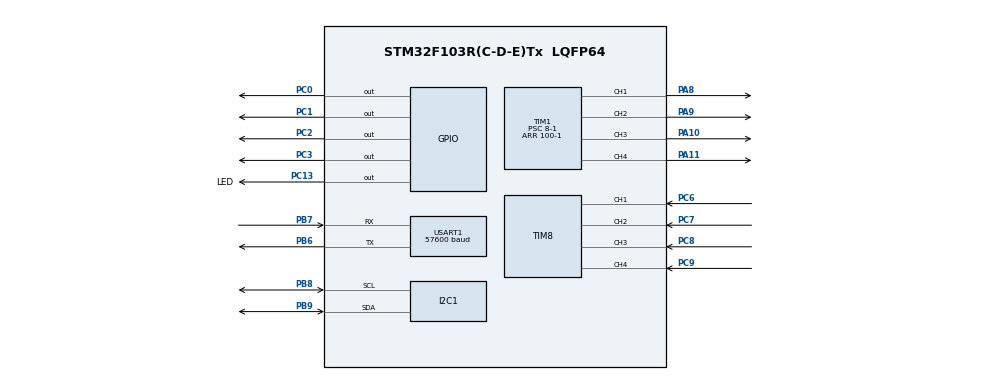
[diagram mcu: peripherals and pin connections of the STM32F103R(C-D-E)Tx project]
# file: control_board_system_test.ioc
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Dma.Request0=USART1_TX
Dma.Request1=USART1_RX
Dma.USART1_RX.1.Direction=DMA_PERIPH_TO_MEMORY
Dma.USART1_RX.1.Instance=DMA1_Channel5
Dma.USART1_RX.1.MemDataAlignment=DMA_MDATAALIGN_BYTE
Dma.USART1_RX.1.MemInc=DMA_MINC_ENABLE
Dma.USART1_RX.1.Mode=DMA_NORMAL
Dma.USART1_RX.1.PeriphDataAlignment=DMA_PDATAALIGN_BYTE
Dma.USART1_RX.1.PeriphInc=DMA_PINC_DISABLE
Dma.USART1_RX.1.Priority=DMA_PRIORITY_HIGH
Dma.USART1_TX.0.Direction=DMA_MEMORY_TO_PERIPH
Dma.USART1_TX.0.Instance=DMA1_Channel4
Dma.USART1_TX.0.MemDataAlignment=DMA_MDATAALIGN_BYTE
Dma.USART1_TX.0.MemInc=DMA_MINC_ENABLE
Dma.USART1_TX.0.Mode=DMA_NORMAL
Dma.USART1_TX.0.PeriphDataAlignment=DMA_PDATAALIGN_BYTE
Dma.USART1_TX.0.PeriphInc=DMA_PINC_DISABLE
Dma.USART1_TX.0.Priority=DMA_PRIORITY_HIGH
I2C1.I2C_Mode=I2C_Fast
Mcu.Family=STM32F1
Mcu.Name=STM32F103R(C-D-E)Tx
Mcu.Package=LQFP64
NVIC.DMA1_Channel4_IRQn=true\:0\:0\:false\:false\:true\:false\:true\:true
NVIC.DMA1_Channel5_IRQn=true\:0\:0\:false\:false\:true\:false\:true\:true
NVIC.PriorityGroup=NVIC_PRIORITYGROUP_4
NVIC.TIM8_CC_IRQn=true\:0\:0\:false\:false\:true\:true\:true\:true
NVIC.USART1_IRQn=true\:0\:0\:false\:false\:true\:true\:true\:true
PA10.Signal=S_TIM1_CH3
PA11.Signal=S_TIM1_CH4
PA13.Mode=Serial_Wire
PA13.Signal=SYS_JTMS-SWDIO
PA14.Mode=Serial_Wire
PA14.Signal=SYS_JTCK-SWCLK
PA8.Signal=S_TIM1_CH1
PA9.Signal=S_TIM1_CH2
PB6.Mode=Asynchronous
PB6.Signal=USART1_TX
PB7.Mode=Asynchronous
PB7.Signal=USART1_RX
PB8.Mode=I2C
PB8.Signal=I2C1_SCL
PB9.Mode=I2C
PB9.Signal=I2C1_SDA
PC0.Signal=GPIO_Output
PC1.Signal=GPIO_Output
PC13-TAMPER-RTC.GPIO_Label=LED
PC13-TAMPER-RTC.PinState=GPIO_PIN_SET
PC13-TAMPER-RTC.Signal=GPIO_Output
PC2.Signal=GPIO_Output
PC3.Signal=GPIO_Output
PC6.Signal=S_TIM8_CH1
PC7.Signal=S_TIM8_CH2
PC8.Signal=S_TIM8_CH3
PC9.Signal=S_TIM8_CH4
PD0-OSC_IN.Mode=HSE-External-Oscillator
PD0-OSC_IN.Signal=RCC_OSC_IN
PD1-OSC_OUT.Mode=HSE-External-Oscillator
PD1-OSC_OUT.Signal=RCC_OSC_OUT
ProjectManager.HeapSize=0x200
ProjectManager.StackSize=0x400
ProjectManager.TargetToolchain=STM32CubeIDE
RCC.AHBFreq_Value=32000000
RCC.APB1Freq_Value=32000000
RCC.APB1TimFreq_Value=32000000
RCC.APB2Freq_Value=32000000
RCC.APB2TimFreq_Value=32000000
RCC.HCLKFreq_Value=32000000
RCC.PLLMUL=RCC_PLL_MUL8
RCC.SYSCLKFreq_VALUE=32000000
RCC.SYSCLKSource=RCC_SYSCLKSOURCE_PLLCLK
RCC.USBFreq_Value=32000000
SH.S_TIM1_CH1.0=TIM1_CH1,PWM Generation1 CH1
SH.S_TIM1_CH2.0=TIM1_CH2,PWM Generation2 CH2
SH.S_TIM1_CH3.0=TIM1_CH3,PWM Generation3 CH3
SH.S_TIM1_CH4.0=TIM1_CH4,PWM Generation4 CH4
SH.S_TIM8_CH1.0=TIM8_CH1,Input_Capture1_from_TI1
SH.S_TIM8_CH2.0=TIM8_CH2,Input_Capture2_from_TI2
SH.S_TIM8_CH3.0=TIM8_CH3,Input_Capture3_from_TI3
SH.S_TIM8_CH4.0=TIM8_CH4,Input_Capture4_from_TI4
TIM1.Channel-PWM\ Generation1\ CH1=TIM_CHANNEL_1
TIM1.Channel-PWM\ Generation2\ CH2=TIM_CHANNEL_2
TIM1.Channel-PWM\ Generation3\ CH3=TIM_CHANNEL_3
TIM1.Channel-PWM\ Generation4\ CH4=TIM_CHANNEL_4
TIM1.Period=100-1
TIM1.Prescaler=8-1
TIM8.Channel-Input_Capture1_from_TI1=TIM_CHANNEL_1
TIM8.Channel-Input_Capture2_from_TI2=TIM_CHANNEL_2
TIM8.Channel-Input_Capture3_from_TI3=TIM_CHANNEL_3
TIM8.Channel-Input_Capture4_from_TI4=TIM_CHANNEL_4
TIM8.ICFilter_CH1=15
TIM8.ICFilter_CH2=15
TIM8.ICFilter_CH3=15
TIM8.ICFilter_CH4=15
USART1.BaudRate=57600
USART1.VirtualMode=VM_ASYNC
VP_TIM1_VS_ClockSourceINT.Mode=Internal
VP_TIM8_VS_ClockSourceINT.Mode=Internal
board=custom

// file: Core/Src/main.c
/* USER CODE BEGIN Header */
/**
  ******************************************************************************
  * @file           : main.c
  * @brief          : Main program body
  ******************************************************************************
  * @attention
  *
  * Copyright (c) 2024 STMicroelectronics.
  * All rights reserved.
  *
  * This software is licensed under terms that can be found in the LICENSE file
  * in the root directory of this software component.
  * If no LICENSE file comes with this software, it is provided AS-IS.
  *
  ******************************************************************************
  */
/* USER CODE END Header */
#include "main.h"

/* USER CODE BEGIN Includes */
#include "mainpp.h"
/* USER CODE END Includes */

I2C_HandleTypeDef hi2c1;

TIM_HandleTypeDef htim_motor;
TIM_HandleTypeDef htim_encoder;

UART_HandleTypeDef huart_rosserial;
DMA_HandleTypeDef hdma_usart1_tx;
DMA_HandleTypeDef hdma_usart1_rx;

void SystemClock_Config(void);
static void MX_GPIO_Init(void);
static void MX_DMA_Init(void);
static void MX_TIM1_Init(void);
static void MX_TIM8_Init(void);
static void MX_USART1_UART_Init(void);
static void MX_I2C1_Init(void);

int main(void)
{

  /* MCU Configuration--------------------------------------------------------*/

  /* Reset of all peripherals, Initializes the Flash interface and the Systick. */
  HAL_Init();

  /* Configure the system clock */
  SystemClock_Config();

  /* Initialize all configured peripherals */
  MX_GPIO_Init();
  MX_DMA_Init();
  MX_TIM1_Init();
  MX_TIM8_Init();
  MX_USART1_UART_Init();
  MX_I2C1_Init();
  /* USER CODE BEGIN 2 */
  setup();
  /* USER CODE END 2 */

  /* Infinite loop */
  while (1)
  {

    /* USER CODE BEGIN 3 */
	  loop();
  }
  /* USER CODE END 3 */
}

void SystemClock_Config(void)
{
  RCC_OscInitTypeDef RCC_OscInitStruct = {0};
  RCC_ClkInitTypeDef RCC_ClkInitStruct = {0};

  /** Initializes the RCC Oscillators according to the specified parameters
  * in the RCC_OscInitTypeDef structure.
  */
  RCC_OscInitStruct.OscillatorType = RCC_OSCILLATORTYPE_HSI;
  RCC_OscInitStruct.HSIState = RCC_HSI_ON;
  RCC_OscInitStruct.HSICalibrationValue = RCC_HSICALIBRATION_DEFAULT;
  RCC_OscInitStruct.PLL.PLLState = RCC_PLL_NONE;
  if (HAL_RCC_OscConfig(&RCC_OscInitStruct) != HAL_OK)
  {
    Error_Handler();
  }

  /** Initializes the CPU, AHB and APB buses clocks
  */
  RCC_ClkInitStruct.ClockType = RCC_CLOCKTYPE_HCLK|RCC_CLOCKTYPE_SYSCLK
                              |RCC_CLOCKTYPE_PCLK1|RCC_CLOCKTYPE_PCLK2;
  RCC_ClkInitStruct.SYSCLKSource = RCC_SYSCLKSOURCE_HSI;
  RCC_ClkInitStruct.AHBCLKDivider = RCC_SYSCLK_DIV1;
  RCC_ClkInitStruct.APB1CLKDivider = RCC_HCLK_DIV1;
  RCC_ClkInitStruct.APB2CLKDivider = RCC_HCLK_DIV1;

  if (HAL_RCC_ClockConfig(&RCC_ClkInitStruct, FLASH_LATENCY_0) != HAL_OK)
  {
    Error_Handler();
  }
}

static void MX_I2C1_Init(void)
{

  hi2c1.Instance = I2C1;
  hi2c1.Init.ClockSpeed = 400000;
  hi2c1.Init.DutyCycle = I2C_DUTYCYCLE_2;
  hi2c1.Init.OwnAddress1 = 0;
  hi2c1.Init.AddressingMode = I2C_ADDRESSINGMODE_7BIT;
  hi2c1.Init.DualAddressMode = I2C_DUALADDRESS_DISABLE;
  hi2c1.Init.OwnAddress2 = 0;
  hi2c1.Init.GeneralCallMode = I2C_GENERALCALL_DISABLE;
  hi2c1.Init.NoStretchMode = I2C_NOSTRETCH_DISABLE;
  if (HAL_I2C_Init(&hi2c1) != HAL_OK)
  {
    Error_Handler();
  }

}

static void MX_TIM1_Init(void)
{

  TIM_ClockConfigTypeDef sClockSourceConfig = {0};
  TIM_MasterConfigTypeDef sMasterConfig = {0};
  TIM_OC_InitTypeDef sConfigOC = {0};
  TIM_BreakDeadTimeConfigTypeDef sBreakDeadTimeConfig = {0};

  htim_motor.Instance = TIM1;
  htim_motor.Init.Prescaler = 8-1;
  htim_motor.Init.CounterMode = TIM_COUNTERMODE_UP;
  htim_motor.Init.Period = 100-1;
  htim_motor.Init.ClockDivision = TIM_CLOCKDIVISION_DIV1;
  htim_motor.Init.RepetitionCounter = 0;
  htim_motor.Init.AutoReloadPreload = TIM_AUTORELOAD_PRELOAD_DISABLE;
  if (HAL_TIM_Base_Init(&htim_motor) != HAL_OK)
  {
    Error_Handler();
  }
  sClockSourceConfig.ClockSource = TIM_CLOCKSOURCE_INTERNAL;
  if (HAL_TIM_ConfigClockSource(&htim_motor, &sClockSourceConfig) != HAL_OK)
  {
    Error_Handler();
  }
  if (HAL_TIM_PWM_Init(&htim_motor) != HAL_OK)
  {
    Error_Handler();
  }
  sMasterConfig.MasterOutputTrigger = TIM_TRGO_RESET;
  sMasterConfig.MasterSlaveMode = TIM_MASTERSLAVEMODE_DISABLE;
  if (HAL_TIMEx_MasterConfigSynchronization(&htim_motor, &sMasterConfig) != HAL_OK)
  {
    Error_Handler();
  }
  sConfigOC.OCMode = TIM_OCMODE_PWM1;
  sConfigOC.Pulse = 0;
  sConfigOC.OCPolarity = TIM_OCPOLARITY_HIGH;
  sConfigOC.OCNPolarity = TIM_OCNPOLARITY_HIGH;
  sConfigOC.OCFastMode = TIM_OCFAST_DISABLE;
  sConfigOC.OCIdleState = TIM_OCIDLESTATE_RESET;
  sConfigOC.OCNIdleState = TIM_OCNIDLESTATE_RESET;
  if (HAL_TIM_PWM_ConfigChannel(&htim_motor, &sConfigOC, TIM_CHANNEL_1) != HAL_OK)
  {
    Error_Handler();
  }
  if (HAL_TIM_PWM_ConfigChannel(&htim_motor, &sConfigOC, TIM_CHANNEL_2) != HAL_OK)
  {
    Error_Handler();
  }
  if (HAL_TIM_PWM_ConfigChannel(&htim_motor, &sConfigOC, TIM_CHANNEL_3) != HAL_OK)
  {
    Error_Handler();
  }
  if (HAL_TIM_PWM_ConfigChannel(&htim_motor, &sConfigOC, TIM_CHANNEL_4) != HAL_OK)
  {
    Error_Handler();
  }
  sBreakDeadTimeConfig.OffStateRunMode = TIM_OSSR_DISABLE;
  sBreakDeadTimeConfig.OffStateIDLEMode = TIM_OSSI_DISABLE;
  sBreakDeadTimeConfig.LockLevel = TIM_LOCKLEVEL_OFF;
  sBreakDeadTimeConfig.DeadTime = 0;
  sBreakDeadTimeConfig.BreakState = TIM_BREAK_DISABLE;
  sBreakDeadTimeConfig.BreakPolarity = TIM_BREAKPOLARITY_HIGH;
  sBreakDeadTimeConfig.AutomaticOutput = TIM_AUTOMATICOUTPUT_DISABLE;
  if (HAL_TIMEx_ConfigBreakDeadTime(&htim_motor, &sBreakDeadTimeConfig) != HAL_OK)
  {
    Error_Handler();
  }
  HAL_TIM_MspPostInit(&htim_motor);

}

static void MX_TIM8_Init(void)
{

  TIM_ClockConfigTypeDef sClockSourceConfig = {0};
  TIM_MasterConfigTypeDef sMasterConfig = {0};
  TIM_IC_InitTypeDef sConfigIC = {0};

  htim_encoder.Instance = TIM8;
  htim_encoder.Init.Prescaler = 0;
  htim_encoder.Init.CounterMode = TIM_COUNTERMODE_UP;
  htim_encoder.Init.Period = 65535;
  htim_encoder.Init.ClockDivision = TIM_CLOCKDIVISION_DIV1;
  htim_encoder.Init.RepetitionCounter = 0;
  htim_encoder.Init.AutoReloadPreload = TIM_AUTORELOAD_PRELOAD_DISABLE;
  if (HAL_TIM_Base_Init(&htim_encoder) != HAL_OK)
  {
    Error_Handler();
  }
  sClockSourceConfig.ClockSource = TIM_CLOCKSOURCE_INTERNAL;
  if (HAL_TIM_ConfigClockSource(&htim_encoder, &sClockSourceConfig) != HAL_OK)
  {
    Error_Handler();
  }
  if (HAL_TIM_IC_Init(&htim_encoder) != HAL_OK)
  {
    Error_Handler();
  }
  sMasterConfig.MasterOutputTrigger = TIM_TRGO_RESET;
  sMasterConfig.MasterSlaveMode = TIM_MASTERSLAVEMODE_DISABLE;
  if (HAL_TIMEx_MasterConfigSynchronization(&htim_encoder, &sMasterConfig) != HAL_OK)
  {
    Error_Handler();
  }
  sConfigIC.ICPolarity = TIM_INPUTCHANNELPOLARITY_RISING;
  sConfigIC.ICSelection = TIM_ICSELECTION_DIRECTTI;
  sConfigIC.ICPrescaler = TIM_ICPSC_DIV1;
  sConfigIC.ICFilter = 15;
  if (HAL_TIM_IC_ConfigChannel(&htim_encoder, &sConfigIC, TIM_CHANNEL_1) != HAL_OK)
  {
    Error_Handler();
  }
  if (HAL_TIM_IC_ConfigChannel(&htim_encoder, &sConfigIC, TIM_CHANNEL_2) != HAL_OK)
  {
    Error_Handler();
  }
  if (HAL_TIM_IC_ConfigChannel(&htim_encoder, &sConfigIC, TIM_CHANNEL_3) != HAL_OK)
  {
    Error_Handler();
  }
  if (HAL_TIM_IC_ConfigChannel(&htim_encoder, &sConfigIC, TIM_CHANNEL_4) != HAL_OK)
  {
    Error_Handler();
  }

}

static void MX_USART1_UART_Init(void)
{

  huart_rosserial.Instance = USART1;
  huart_rosserial.Init.BaudRate = 115200;
  huart_rosserial.Init.WordLength = UART_WORDLENGTH_8B;
  huart_rosserial.Init.StopBits = UART_STOPBITS_1;
  huart_rosserial.Init.Parity = UART_PARITY_NONE;
  huart_rosserial.Init.Mode = UART_MODE_TX_RX;
  huart_rosserial.Init.HwFlowCtl = UART_HWCONTROL_NONE;
  huart_rosserial.Init.OverSampling = UART_OVERSAMPLING_16;
  if (HAL_UART_Init(&huart_rosserial) != HAL_OK)
  {
    Error_Handler();
  }

}

static void MX_DMA_Init(void)
{

  /* DMA controller clock enable */
  __HAL_RCC_DMA1_CLK_ENABLE();

  /* DMA interrupt init */
  /* DMA1_Channel4_IRQn interrupt configuration */
  HAL_NVIC_SetPriority(DMA1_Channel4_IRQn, 0, 0);
  HAL_NVIC_EnableIRQ(DMA1_Channel4_IRQn);
  /* DMA1_Channel5_IRQn interrupt configuration */
  HAL_NVIC_SetPriority(DMA1_Channel5_IRQn, 0, 0);
  HAL_NVIC_EnableIRQ(DMA1_Channel5_IRQn);

}

static void MX_GPIO_Init(void)
{
  GPIO_InitTypeDef GPIO_InitStruct = {0};

  /* GPIO Ports Clock Enable */
  __HAL_RCC_GPIOC_CLK_ENABLE();
  __HAL_RCC_GPIOD_CLK_ENABLE();
  __HAL_RCC_GPIOA_CLK_ENABLE();
  __HAL_RCC_GPIOB_CLK_ENABLE();

  /*Configure GPIO pin Output Level */
  HAL_GPIO_WritePin(LED_GPIO_Port, LED_Pin, GPIO_PIN_SET);

  /*Configure GPIO pin Output Level */
  HAL_GPIO_WritePin(GPIOC, GPIO_PIN_0|GPIO_PIN_1|GPIO_PIN_2|GPIO_PIN_3, GPIO_PIN_RESET);

  /*Configure GPIO pins : LED_Pin PC0 PC1 PC2
                           PC3 */
  GPIO_InitStruct.Pin = LED_Pin|GPIO_PIN_0|GPIO_PIN_1|GPIO_PIN_2
                          |GPIO_PIN_3;
  GPIO_InitStruct.Mode = GPIO_MODE_OUTPUT_PP;
  GPIO_InitStruct.Pull = GPIO_NOPULL;
  GPIO_InitStruct.Speed = GPIO_SPEED_FREQ_LOW;
  HAL_GPIO_Init(GPIOC, &GPIO_InitStruct);

}

void Error_Handler(void)
{
  __disable_irq();
  while (1)
  {
  }
}
